VERSION 5.8 ;
BUSBITCHARS "[]" ;
DIVIDERCHAR "/" ;
UNITS
    DATABASE MICRONS 1000 ;
END UNITS

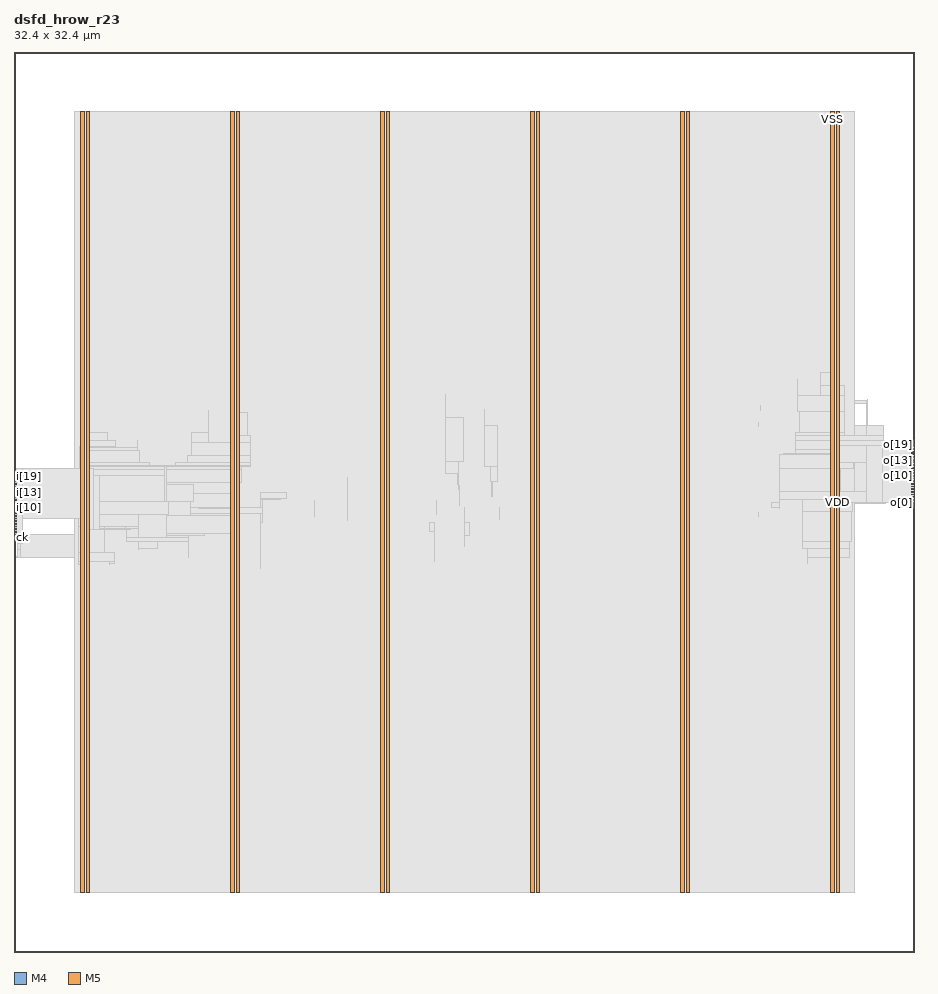
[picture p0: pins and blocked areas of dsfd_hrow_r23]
MACRO dsfd_hrow_r23
  FOREIGN dsfd_hrow_r23 0 0 ;
  CLASS BLOCK ;
  SIZE 32.4 BY 32.4 ;
  PIN ck
    DIRECTION INPUT ;
    USE SIGNAL ;
    PORT
      LAYER M4 ;
        RECT  0 14.928 0.084 14.952 ;
    END
  END ck
  PIN i[0]
    DIRECTION INPUT ;
    USE SIGNAL ;
    PORT
      LAYER M4 ;
        RECT  0 15.024 0.084 15.048 ;
    END
  END i[0]
  PIN i[10]
    DIRECTION INPUT ;
    USE SIGNAL ;
    PORT
      LAYER M4 ;
        RECT  0 15.984 0.084 16.008 ;
    END
  END i[10]
  PIN i[11]
    DIRECTION INPUT ;
    USE SIGNAL ;
    PORT
      LAYER M4 ;
        RECT  0 16.08 0.084 16.104 ;
    END
  END i[11]
  PIN i[12]
    DIRECTION INPUT ;
    USE SIGNAL ;
    PORT
      LAYER M4 ;
        RECT  0 16.176 0.084 16.2 ;
    END
  END i[12]
  PIN i[13]
    DIRECTION INPUT ;
    USE SIGNAL ;
    PORT
      LAYER M4 ;
        RECT  0 16.272 0.084 16.296 ;
    END
  END i[13]
  PIN i[14]
    DIRECTION INPUT ;
    USE SIGNAL ;
    PORT
      LAYER M4 ;
        RECT  0 16.368 0.084 16.392 ;
    END
  END i[14]
  PIN i[15]
    DIRECTION INPUT ;
    USE SIGNAL ;
    PORT
      LAYER M4 ;
        RECT  0 16.464 0.084 16.488 ;
    END
  END i[15]
  PIN i[16]
    DIRECTION INPUT ;
    USE SIGNAL ;
    PORT
      LAYER M4 ;
        RECT  0 16.56 0.084 16.584 ;
    END
  END i[16]
  PIN i[17]
    DIRECTION INPUT ;
    USE SIGNAL ;
    PORT
      LAYER M4 ;
        RECT  0 16.656 0.084 16.68 ;
    END
  END i[17]
  PIN i[18]
    DIRECTION INPUT ;
    USE SIGNAL ;
    PORT
      LAYER M4 ;
        RECT  0 16.752 0.084 16.776 ;
    END
  END i[18]
  PIN i[19]
    DIRECTION INPUT ;
    USE SIGNAL ;
    PORT
      LAYER M4 ;
        RECT  0 16.848 0.084 16.872 ;
    END
  END i[19]
  PIN i[1]
    DIRECTION INPUT ;
    USE SIGNAL ;
    PORT
      LAYER M4 ;
        RECT  0 15.12 0.084 15.144 ;
    END
  END i[1]
  PIN i[20]
    DIRECTION INPUT ;
    USE SIGNAL ;
    PORT
      LAYER M4 ;
        RECT  0 16.944 0.084 16.968 ;
    END
  END i[20]
  PIN i[21]
    DIRECTION INPUT ;
    USE SIGNAL ;
    PORT
      LAYER M4 ;
        RECT  0 17.04 0.084 17.064 ;
    END
  END i[21]
  PIN i[22]
    DIRECTION INPUT ;
    USE SIGNAL ;
    PORT
      LAYER M4 ;
        RECT  0 17.136 0.084 17.16 ;
    END
  END i[22]
  PIN i[2]
    DIRECTION INPUT ;
    USE SIGNAL ;
    PORT
      LAYER M4 ;
        RECT  0 15.216 0.084 15.24 ;
    END
  END i[2]
  PIN i[3]
    DIRECTION INPUT ;
    USE SIGNAL ;
    PORT
      LAYER M4 ;
        RECT  0 15.312 0.084 15.336 ;
    END
  END i[3]
  PIN i[4]
    DIRECTION INPUT ;
    USE SIGNAL ;
    PORT
      LAYER M4 ;
        RECT  0 15.408 0.084 15.432 ;
    END
  END i[4]
  PIN i[5]
    DIRECTION INPUT ;
    USE SIGNAL ;
    PORT
      LAYER M4 ;
        RECT  0 15.504 0.084 15.528 ;
    END
  END i[5]
  PIN i[6]
    DIRECTION INPUT ;
    USE SIGNAL ;
    PORT
      LAYER M4 ;
        RECT  0 15.6 0.084 15.624 ;
    END
  END i[6]
  PIN i[7]
    DIRECTION INPUT ;
    USE SIGNAL ;
    PORT
      LAYER M4 ;
        RECT  0 15.696 0.084 15.72 ;
    END
  END i[7]
  PIN i[8]
    DIRECTION INPUT ;
    USE SIGNAL ;
    PORT
      LAYER M4 ;
        RECT  0 15.792 0.084 15.816 ;
    END
  END i[8]
  PIN i[9]
    DIRECTION INPUT ;
    USE SIGNAL ;
    PORT
      LAYER M4 ;
        RECT  0 15.888 0.084 15.912 ;
    END
  END i[9]
  PIN o[0]
    DIRECTION OUTPUT ;
    USE SIGNAL ;
    PORT
      LAYER M4 ;
        RECT  32.316 16.176 32.4 16.2 ;
    END
  END o[0]
  PIN o[10]
    DIRECTION OUTPUT ;
    USE SIGNAL ;
    PORT
      LAYER M4 ;
        RECT  32.316 17.136 32.4 17.16 ;
    END
  END o[10]
  PIN o[11]
    DIRECTION OUTPUT ;
    USE SIGNAL ;
    PORT
      LAYER M4 ;
        RECT  32.316 17.232 32.4 17.256 ;
    END
  END o[11]
  PIN o[12]
    DIRECTION OUTPUT ;
    USE SIGNAL ;
    PORT
      LAYER M4 ;
        RECT  32.316 17.328 32.4 17.352 ;
    END
  END o[12]
  PIN o[13]
    DIRECTION OUTPUT ;
    USE SIGNAL ;
    PORT
      LAYER M4 ;
        RECT  32.316 17.424 32.4 17.448 ;
    END
  END o[13]
  PIN o[14]
    DIRECTION OUTPUT ;
    USE SIGNAL ;
    PORT
      LAYER M4 ;
        RECT  32.316 17.52 32.4 17.544 ;
    END
  END o[14]
  PIN o[15]
    DIRECTION OUTPUT ;
    USE SIGNAL ;
    PORT
      LAYER M4 ;
        RECT  32.316 17.616 32.4 17.64 ;
    END
  END o[15]
  PIN o[16]
    DIRECTION OUTPUT ;
    USE SIGNAL ;
    PORT
      LAYER M4 ;
        RECT  32.316 17.712 32.4 17.736 ;
    END
  END o[16]
  PIN o[17]
    DIRECTION OUTPUT ;
    USE SIGNAL ;
    PORT
      LAYER M4 ;
        RECT  32.316 17.808 32.4 17.832 ;
    END
  END o[17]
  PIN o[18]
    DIRECTION OUTPUT ;
    USE SIGNAL ;
    PORT
      LAYER M4 ;
        RECT  32.316 17.904 32.4 17.928 ;
    END
  END o[18]
  PIN o[19]
    DIRECTION OUTPUT ;
    USE SIGNAL ;
    PORT
      LAYER M4 ;
        RECT  32.316 18 32.4 18.024 ;
    END
  END o[19]
  PIN o[1]
    DIRECTION OUTPUT ;
    USE SIGNAL ;
    PORT
      LAYER M4 ;
        RECT  32.316 16.272 32.4 16.296 ;
    END
  END o[1]
  PIN o[20]
    DIRECTION OUTPUT ;
    USE SIGNAL ;
    PORT
      LAYER M4 ;
        RECT  32.316 18.096 32.4 18.12 ;
    END
  END o[20]
  PIN o[21]
    DIRECTION OUTPUT ;
    USE SIGNAL ;
    PORT
      LAYER M4 ;
        RECT  32.316 18.192 32.4 18.216 ;
    END
  END o[21]
  PIN o[22]
    DIRECTION OUTPUT ;
    USE SIGNAL ;
    PORT
      LAYER M4 ;
        RECT  32.316 18.288 32.4 18.312 ;
    END
  END o[22]
  PIN o[2]
    DIRECTION OUTPUT ;
    USE SIGNAL ;
    PORT
      LAYER M4 ;
        RECT  32.316 16.368 32.4 16.392 ;
    END
  END o[2]
  PIN o[3]
    DIRECTION OUTPUT ;
    USE SIGNAL ;
    PORT
      LAYER M4 ;
        RECT  32.316 16.464 32.4 16.488 ;
    END
  END o[3]
  PIN o[4]
    DIRECTION OUTPUT ;
    USE SIGNAL ;
    PORT
      LAYER M4 ;
        RECT  32.316 16.56 32.4 16.584 ;
    END
  END o[4]
  PIN o[5]
    DIRECTION OUTPUT ;
    USE SIGNAL ;
    PORT
      LAYER M4 ;
        RECT  32.316 16.656 32.4 16.68 ;
    END
  END o[5]
  PIN o[6]
    DIRECTION OUTPUT ;
    USE SIGNAL ;
    PORT
      LAYER M4 ;
        RECT  32.316 16.752 32.4 16.776 ;
    END
  END o[6]
  PIN o[7]
    DIRECTION OUTPUT ;
    USE SIGNAL ;
    PORT
      LAYER M4 ;
        RECT  32.316 16.848 32.4 16.872 ;
    END
  END o[7]
  PIN o[8]
    DIRECTION OUTPUT ;
    USE SIGNAL ;
    PORT
      LAYER M4 ;
        RECT  32.316 16.944 32.4 16.968 ;
    END
  END o[8]
  PIN o[9]
    DIRECTION OUTPUT ;
    USE SIGNAL ;
    PORT
      LAYER M4 ;
        RECT  32.316 17.04 32.4 17.064 ;
    END
  END o[9]
  PIN rn
    DIRECTION INPUT ;
    USE SIGNAL ;
    PORT
      LAYER M4 ;
        RECT  0 17.232 0.084 17.256 ;
    END
  END rn
  PIN VDD
    DIRECTION INOUT ;
    USE POWER ;
    PORT
      LAYER M5 ;
        RECT  29.592 2.151 29.712 30.249 ;
        RECT  24.192 2.151 24.312 30.249 ;
        RECT  18.792 2.151 18.912 30.249 ;
        RECT  13.392 2.151 13.512 30.249 ;
        RECT  7.992 2.151 8.112 30.249 ;
        RECT  2.592 2.151 2.712 30.249 ;
    END
  END VDD
  PIN VSS
    DIRECTION INOUT ;
    USE GROUND ;
    PORT
      LAYER M5 ;
        RECT  29.4 2.137 29.52 30.263 ;
        RECT  24 2.137 24.12 30.263 ;
        RECT  18.6 2.137 18.72 30.263 ;
        RECT  13.2 2.137 13.32 30.263 ;
        RECT  7.8 2.137 7.92 30.263 ;
        RECT  2.4 2.137 2.52 30.263 ;
    END
  END VSS
  # OT_OBS_CLOSED layer=M5 d_um=1.536 added=0
  OBS
    LAYER RVTN ;
     RECT  2.16 2.16 30.24 2.295 ;
     RECT  2.16 2.565 30.24 2.835 ;
     RECT  2.16 3.105 30.24 3.375 ;
     RECT  2.16 3.645 30.24 3.915 ;
     RECT  2.16 4.185 30.24 4.455 ;
     RECT  2.16 4.725 30.24 4.995 ;
     RECT  2.16 5.265 30.24 5.535 ;
     RECT  2.16 5.805 30.24 6.075 ;
     RECT  2.16 6.345 30.24 6.615 ;
     RECT  2.16 6.885 30.24 7.155 ;
     RECT  2.16 7.425 30.24 7.695 ;
     RECT  2.16 7.965 30.24 8.235 ;
     RECT  2.16 8.505 30.24 8.775 ;
     RECT  2.16 9.045 30.24 9.315 ;
     RECT  2.16 9.585 30.24 9.855 ;
     RECT  2.16 10.125 30.24 10.395 ;
     RECT  2.16 10.665 30.24 10.935 ;
     RECT  2.16 11.205 30.24 11.475 ;
     RECT  2.16 11.745 30.24 12.015 ;
     RECT  2.16 12.285 30.24 12.555 ;
     RECT  2.16 12.825 30.24 13.095 ;
     RECT  2.16 13.365 30.24 13.635 ;
     RECT  2.16 13.905 30.24 14.175 ;
     RECT  2.16 14.445 30.24 14.715 ;
     RECT  2.16 14.985 30.24 15.255 ;
     RECT  2.16 15.525 30.24 15.795 ;
     RECT  2.16 16.065 30.24 16.335 ;
     RECT  2.16 16.605 30.24 16.875 ;
     RECT  2.16 17.145 30.24 17.415 ;
     RECT  2.16 17.685 30.24 17.955 ;
     RECT  2.16 18.225 30.24 18.495 ;
     RECT  2.16 18.765 30.24 19.035 ;
     RECT  2.16 19.305 30.24 19.575 ;
     RECT  2.16 19.845 30.24 20.115 ;
     RECT  2.16 20.385 30.24 20.655 ;
     RECT  2.16 20.925 30.24 21.195 ;
     RECT  2.16 21.465 30.24 21.735 ;
     RECT  2.16 22.005 30.24 22.275 ;
     RECT  2.16 22.545 30.24 22.815 ;
     RECT  2.16 23.085 30.24 23.355 ;
     RECT  2.16 23.625 30.24 23.895 ;
     RECT  2.16 24.165 30.24 24.435 ;
     RECT  2.16 24.705 30.24 24.975 ;
     RECT  2.16 25.245 30.24 25.515 ;
     RECT  2.16 25.785 30.24 26.055 ;
     RECT  2.16 26.325 30.24 26.595 ;
     RECT  2.16 26.865 30.24 27.135 ;
     RECT  2.16 27.405 30.24 27.675 ;
     RECT  2.16 27.945 30.24 28.215 ;
     RECT  2.16 28.485 30.24 28.755 ;
     RECT  2.16 29.025 30.24 29.295 ;
     RECT  2.16 29.565 30.24 29.835 ;
     RECT  2.16 30.105 30.24 30.24 ;
    LAYER RVTP ;
     RECT  2.16 2.295 30.24 2.565 ;
     RECT  2.16 2.835 30.24 3.105 ;
     RECT  2.16 3.375 30.24 3.645 ;
     RECT  2.16 3.915 30.24 4.185 ;
     RECT  2.16 4.455 30.24 4.725 ;
     RECT  2.16 4.995 30.24 5.265 ;
     RECT  2.16 5.535 30.24 5.805 ;
     RECT  2.16 6.075 30.24 6.345 ;
     RECT  2.16 6.615 30.24 6.885 ;
     RECT  2.16 7.155 30.24 7.425 ;
     RECT  2.16 7.695 30.24 7.965 ;
     RECT  2.16 8.235 30.24 8.505 ;
     RECT  2.16 8.775 30.24 9.045 ;
     RECT  2.16 9.315 30.24 9.585 ;
     RECT  2.16 9.855 30.24 10.125 ;
     RECT  2.16 10.395 30.24 10.665 ;
     RECT  2.16 10.935 30.24 11.205 ;
     RECT  2.16 11.475 30.24 11.745 ;
     RECT  2.16 12.015 30.24 12.285 ;
     RECT  2.16 12.555 30.24 12.825 ;
     RECT  2.16 13.095 30.24 13.365 ;
     RECT  2.16 13.635 30.24 13.905 ;
     RECT  2.16 14.175 30.24 14.445 ;
     RECT  2.16 14.715 30.24 14.985 ;
     RECT  2.16 15.255 30.24 15.525 ;
     RECT  2.16 15.795 30.24 16.065 ;
     RECT  2.16 16.335 30.24 16.605 ;
     RECT  2.16 16.875 30.24 17.145 ;
     RECT  2.16 17.415 30.24 17.685 ;
     RECT  2.16 17.955 30.24 18.225 ;
     RECT  2.16 18.495 30.24 18.765 ;
     RECT  2.16 19.035 30.24 19.305 ;
     RECT  2.16 19.575 30.24 19.845 ;
     RECT  2.16 20.115 30.24 20.385 ;
     RECT  2.16 20.655 30.24 20.925 ;
     RECT  2.16 21.195 30.24 21.465 ;
     RECT  2.16 21.735 30.24 22.005 ;
     RECT  2.16 22.275 30.24 22.545 ;
     RECT  2.16 22.815 30.24 23.085 ;
     RECT  2.16 23.355 30.24 23.625 ;
     RECT  2.16 23.895 30.24 24.165 ;
     RECT  2.16 24.435 30.24 24.705 ;
     RECT  2.16 24.975 30.24 25.245 ;
     RECT  2.16 25.515 30.24 25.785 ;
     RECT  2.16 26.055 30.24 26.325 ;
     RECT  2.16 26.595 30.24 26.865 ;
     RECT  2.16 27.135 30.24 27.405 ;
     RECT  2.16 27.675 30.24 27.945 ;
     RECT  2.16 28.215 30.24 28.485 ;
     RECT  2.16 28.755 30.24 29.025 ;
     RECT  2.16 29.295 30.24 29.565 ;
     RECT  2.16 29.835 30.24 30.105 ;
    LAYER M1 ;
     RECT  2.16 2.151 30.24 30.249 ;
    LAYER M2 ;
     RECT  0.103 14.22 0.139 14.238 ;
     RECT  0.103 16.38 0.139 16.398 ;
     RECT  0.139 14.22 0.247 14.778 ;
     RECT  0.139 16.38 0.535 17.1 ;
     RECT  0.247 14.22 2.16 15.048 ;
     RECT  0.535 16.11 2.16 17.1 ;
     RECT  2.16 2.151 30.24 30.249 ;
     RECT  30.24 19.746 30.695 19.872 ;
     RECT  30.695 19.854 30.731 19.872 ;
     RECT  30.24 16.146 31.307 18.954 ;
     RECT  31.307 16.146 31.343 18.414 ;
     RECT  31.343 16.146 31.379 17.676 ;
     RECT  31.379 16.416 31.415 16.524 ;
     RECT  31.415 16.416 31.451 16.434 ;
    LAYER M3 ;
     RECT  2.415 2.143 2.505 2.413 ;
     RECT  7.815 2.143 7.905 2.413 ;
     RECT  13.215 2.143 13.305 2.413 ;
     RECT  18.615 2.143 18.705 2.413 ;
     RECT  24.015 2.143 24.105 2.413 ;
     RECT  29.415 2.143 29.505 2.413 ;
     RECT  2.415 2.413 2.697 13.945 ;
     RECT  3.42 13.945 3.438 13.981 ;
     RECT  2.304 13.945 2.697 14.071 ;
     RECT  3.42 13.981 3.618 14.071 ;
     RECT  28.548 13.981 28.566 14.215 ;
     RECT  29.415 2.413 29.697 14.215 ;
     RECT  2.304 14.071 3.618 14.369 ;
     RECT  0.108 14.215 0.126 14.485 ;
     RECT  4.464 14.485 4.482 14.521 ;
     RECT  28.548 14.215 30.078 14.521 ;
     RECT  0.108 14.485 0.234 14.719 ;
     RECT  4.464 14.521 5.166 14.791 ;
     RECT  6.264 14.215 6.282 14.791 ;
     RECT  28.368 14.521 30.078 14.791 ;
     RECT  4.032 14.791 6.282 14.909 ;
     RECT  5.472 14.909 6.282 14.989 ;
     RECT  16.2 14.611 16.218 14.989 ;
     RECT  0.108 14.719 0.306 15.053 ;
     RECT  5.472 14.989 6.858 15.061 ;
     RECT  7.815 2.413 8.097 15.061 ;
     RECT  0.144 15.053 0.306 15.149 ;
     RECT  15.12 14.071 15.138 15.151 ;
     RECT  0.18 15.149 0.306 15.245 ;
     RECT  4.032 14.909 4.482 15.259 ;
     RECT  2.304 14.369 3.258 15.331 ;
     RECT  3.996 15.259 4.482 15.331 ;
     RECT  0.216 15.245 0.306 15.341 ;
     RECT  0.252 15.341 0.306 15.437 ;
     RECT  14.94 15.151 15.138 15.449 ;
     RECT  16.2 14.989 16.398 15.449 ;
     RECT  8.856 13.801 8.874 15.457 ;
     RECT  0.288 15.437 0.306 15.533 ;
     RECT  5.472 15.061 8.097 15.719 ;
     RECT  2.304 15.331 4.482 15.763 ;
     RECT  5.472 15.719 5.562 15.763 ;
     RECT  6.336 15.719 8.097 15.799 ;
     RECT  8.856 15.457 8.946 15.799 ;
     RECT  26.784 15.691 26.802 15.827 ;
     RECT  28.368 14.791 30.15 15.871 ;
     RECT  6.336 15.799 8.946 15.989 ;
     RECT  16.2 15.449 16.218 15.989 ;
     RECT  17.46 15.565 17.478 15.989 ;
     RECT  27.54 15.961 27.558 15.997 ;
     RECT  27.252 15.997 27.558 16.169 ;
     RECT  10.8 15.691 10.818 16.259 ;
     RECT  15.192 15.763 15.21 16.259 ;
     RECT  8.856 15.989 8.946 16.303 ;
     RECT  27.54 16.169 27.558 16.303 ;
     RECT  28.368 15.871 30.186 16.303 ;
     RECT  8.856 16.303 9.594 16.339 ;
     RECT  0.54 16.105 0.558 16.375 ;
     RECT  31.356 16.141 31.374 16.411 ;
     RECT  2.304 15.763 5.562 16.507 ;
     RECT  6.336 15.989 8.097 16.507 ;
     RECT  8.856 16.339 9.81 16.529 ;
     RECT  27.54 16.303 30.186 16.589 ;
     RECT  16.02 16.069 16.038 16.645 ;
     RECT  0.108 16.375 0.558 16.685 ;
     RECT  15.984 16.645 16.038 16.799 ;
     RECT  15.984 16.799 16.002 16.843 ;
     RECT  0.108 16.685 0.342 16.877 ;
     RECT  31.356 16.411 31.446 16.877 ;
     RECT  31.356 16.877 31.374 16.879 ;
     RECT  2.304 16.507 8.097 16.915 ;
     RECT  17.208 16.411 17.226 16.951 ;
     RECT  0.108 16.877 0.27 16.973 ;
     RECT  11.988 15.529 12.006 17.069 ;
     RECT  15.948 16.843 16.002 17.221 ;
     RECT  0.108 16.973 0.162 17.261 ;
     RECT  30.708 16.879 31.374 17.357 ;
     RECT  2.304 16.915 8.19 17.375 ;
     RECT  0.108 17.261 0.126 17.405 ;
     RECT  27.54 16.589 29.754 17.419 ;
     RECT  2.34 17.375 8.19 17.491 ;
     RECT  17.136 16.951 17.406 17.491 ;
     RECT  2.34 17.491 8.514 17.519 ;
     RECT  2.34 17.519 4.878 17.609 ;
     RECT  5.796 17.519 8.514 17.609 ;
     RECT  15.516 17.221 16.002 17.653 ;
     RECT  31.248 17.357 31.374 17.837 ;
     RECT  6.228 17.609 8.514 17.879 ;
     RECT  27.54 17.419 30.222 17.915 ;
     RECT  27.684 17.915 30.222 17.951 ;
     RECT  2.34 17.609 4.518 18.059 ;
     RECT  28.116 17.951 30.222 18.091 ;
     RECT  31.248 17.837 31.338 18.091 ;
     RECT  2.34 18.059 4.446 18.149 ;
     RECT  2.34 18.149 3.654 18.185 ;
     RECT  6.372 17.879 8.514 18.329 ;
     RECT  2.415 18.185 3.654 18.419 ;
     RECT  4.428 18.149 4.446 18.419 ;
     RECT  28.116 18.091 31.338 18.419 ;
     RECT  7.776 18.329 8.514 18.599 ;
     RECT  28.116 18.419 31.302 18.599 ;
     RECT  2.415 18.419 3.366 18.689 ;
     RECT  6.372 18.329 7.002 18.689 ;
     RECT  28.116 18.599 29.898 18.689 ;
     RECT  16.92 17.491 17.406 18.959 ;
     RECT  30.672 18.599 31.302 18.959 ;
     RECT  26.784 18.931 26.802 19.067 ;
     RECT  15.516 17.653 16.182 19.229 ;
     RECT  7.776 18.599 8.406 19.409 ;
     RECT  28.26 18.689 29.898 19.471 ;
     RECT  6.984 18.689 7.002 19.499 ;
     RECT  16.92 18.959 16.938 19.535 ;
     RECT  26.856 19.507 26.874 19.679 ;
     RECT  30.672 18.959 30.726 19.769 ;
     RECT  30.708 19.769 30.726 19.877 ;
     RECT  28.188 19.471 29.898 20.039 ;
     RECT  15.516 19.229 15.534 20.075 ;
     RECT  29.016 20.039 29.898 20.381 ;
     RECT  28.188 20.039 28.206 20.615 ;
     RECT  7.776 19.409 8.097 20.849 ;
     RECT  29.016 20.381 29.697 20.849 ;
     RECT  2.415 18.689 2.697 29.987 ;
     RECT  7.815 20.849 8.097 29.987 ;
     RECT  13.215 2.413 13.497 29.987 ;
     RECT  18.615 2.413 18.897 29.987 ;
     RECT  24.015 2.413 24.297 29.987 ;
     RECT  29.415 20.849 29.697 29.987 ;
     RECT  2.415 29.987 2.505 30.257 ;
     RECT  7.815 29.987 7.905 30.257 ;
     RECT  13.215 29.987 13.305 30.257 ;
     RECT  18.615 29.987 18.705 30.257 ;
     RECT  24.015 29.987 24.105 30.257 ;
     RECT  29.415 29.987 29.505 30.257 ;
    LAYER M4 ;
     RECT  0.06 14.928 0.097 17.256 ;
     RECT  0.097 14.928 0.323 17.4 ;
     RECT  0.323 15.6 2.408 17.4 ;
     RECT  2.408 2.148 2.512 30.252 ;
     RECT  2.512 2.418 2.704 29.982 ;
     RECT  2.704 15.216 2.873 17.4 ;
     RECT  2.873 15.216 3.089 17.16 ;
     RECT  3.089 15.216 4.205 15.24 ;
     RECT  3.089 16.224 5.42 17.16 ;
     RECT  5.42 16.224 5.507 17.496 ;
     RECT  5.507 16.224 6.473 16.824 ;
     RECT  6.649 15.984 7.808 16.008 ;
     RECT  7.808 2.148 7.912 30.252 ;
     RECT  7.912 2.418 8.104 29.982 ;
     RECT  13.208 2.148 13.312 30.252 ;
     RECT  13.312 2.418 13.504 29.982 ;
     RECT  18.608 2.148 18.712 30.252 ;
     RECT  18.712 2.418 18.904 29.982 ;
     RECT  24.008 2.148 24.112 30.252 ;
     RECT  24.112 2.418 24.304 29.982 ;
     RECT  29.365 15.984 29.408 16.008 ;
     RECT  29.408 2.148 29.512 30.252 ;
     RECT  29.512 2.418 29.704 29.982 ;
     RECT  29.704 16.176 30.697 16.584 ;
     RECT  29.704 17.616 30.697 18.216 ;
     RECT  30.697 16.176 31.273 18.216 ;
     RECT  31.273 16.176 32.364 18.312 ;
    LAYER M5 ;
     RECT  2.4 2.137 2.52 2.151 ;
     RECT  7.8 2.137 7.92 2.151 ;
     RECT  13.2 2.137 13.32 2.151 ;
     RECT  18.6 2.137 18.72 2.151 ;
     RECT  24 2.137 24.12 2.151 ;
     RECT  29.4 2.137 29.52 2.151 ;
     RECT  0.288 14.917 0.312 17.171 ;
     RECT  5.472 16.213 5.496 17.507 ;
     RECT  2.4 2.151 2.712 30.249 ;
     RECT  7.8 2.151 8.112 30.249 ;
     RECT  13.2 2.151 13.512 30.249 ;
     RECT  18.6 2.151 18.912 30.249 ;
     RECT  24 2.151 24.312 30.249 ;
     RECT  29.4 2.151 29.712 30.249 ;
     RECT  2.4 30.249 2.52 30.263 ;
     RECT  7.8 30.249 7.92 30.263 ;
     RECT  13.2 30.249 13.32 30.263 ;
     RECT  18.6 30.249 18.72 30.263 ;
     RECT  24 30.249 24.12 30.263 ;
     RECT  29.4 30.249 29.52 30.263 ;
  END
END dsfd_hrow_r23
END LIBRARY
